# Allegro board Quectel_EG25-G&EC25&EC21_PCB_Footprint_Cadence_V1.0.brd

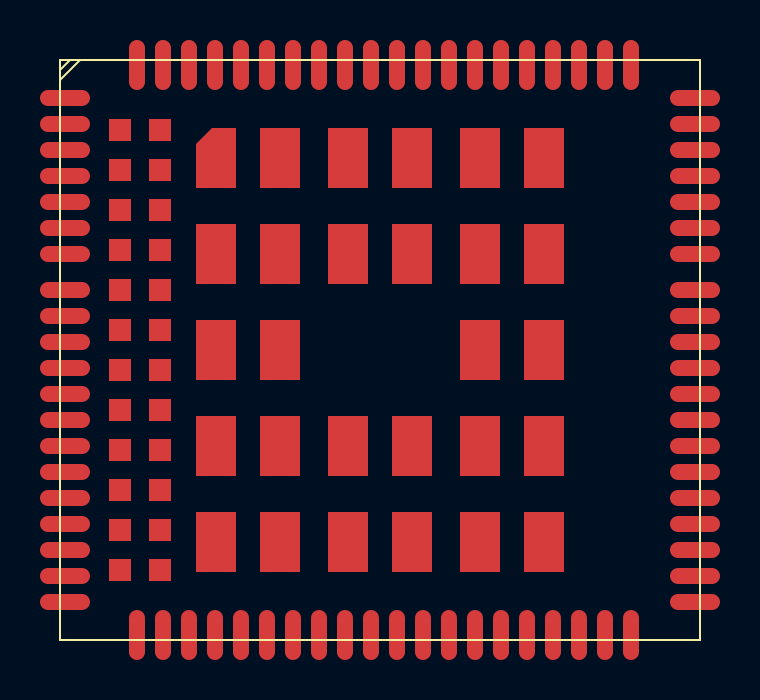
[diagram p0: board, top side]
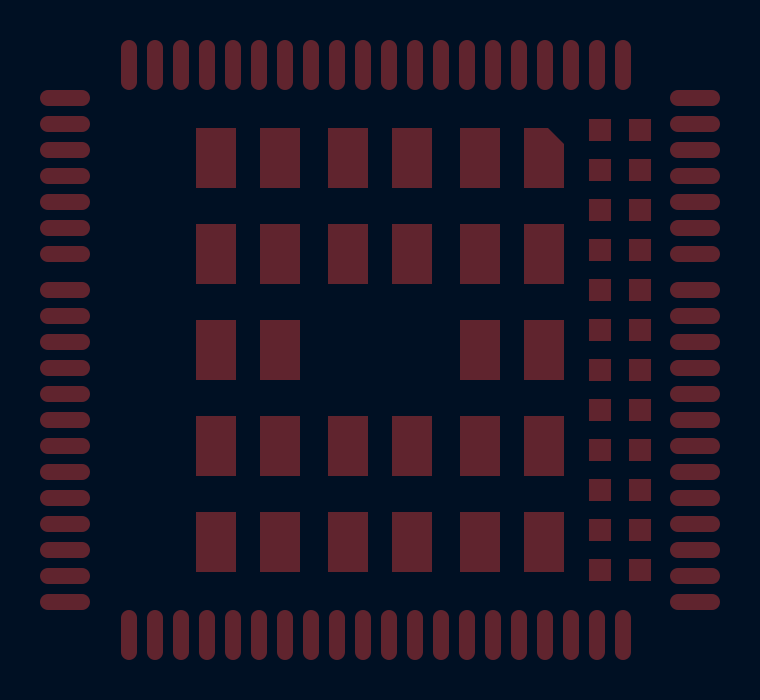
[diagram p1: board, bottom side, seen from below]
No outline. copper layers: TOP, BOTTOM. Coordinates in mm from the lowest, leftmost part position.

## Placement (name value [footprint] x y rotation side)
NOREF  -  [unnamed]  0 0 0 top

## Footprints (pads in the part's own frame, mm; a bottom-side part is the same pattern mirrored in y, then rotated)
unnamed
  oval 2.5x0.8 smd: 1(-15.75,12.6) 2(-15.75,11.3) 3(-15.75,10) 4(-15.75,8.7) 5(-15.75,7.4) 6(-15.75,6.1) 7(-15.75,4.8) 8(-15.75,0.4) 9(-15.75,-0.9) 10(-15.75,-2.2) 11(-15.75,-3.5) 12(-15.75,-4.8) 13(-15.75,-6.1) 14(-15.75,-7.4) 15(-15.75,-8.7) 16(-15.75,-10) 17(-15.75,-11.3) 18(-15.75,-12.6) 37(15.75,-12.6) 38(15.75,-11.3) 39(15.75,-10) 40(15.75,-8.7) 41(15.75,-7.4) 42(15.75,-6.1) 43(15.75,-4.8) 44(15.75,-3.5) 45(15.75,-2.2) 46(15.75,-0.9) 47(15.75,0.4) 48(15.75,4.8) 49(15.75,6.1) 50(15.75,7.4) 51(15.75,8.7) 52(15.75,10) 53(15.75,11.3) 54(15.75,12.6) 141(-15.75,3) 142(-15.75,1.7) 143(15.75,1.7) 144(15.75,3)
  oval 0.8x2.5 smd: 19(-9.55,-14.25) 20(-8.25,-14.25) 21(-6.95,-14.25) 22(-5.65,-14.25) 23(-4.35,-14.25) 24(-3.05,-14.25) 25(-1.75,-14.25) 26(-0.45,-14.25) 27(0.85,-14.25) 28(2.15,-14.25) 29(3.45,-14.25) 30(4.75,-14.25) 31(6.05,-14.25) 32(7.35,-14.25) 33(8.65,-14.25) 34(9.95,-14.25) 35(11.25,-14.25) 36(12.55,-14.25) 55(12.55,14.25) 56(11.25,14.25) 57(9.95,14.25) 58(8.65,14.25) 59(7.35,14.25) 60(6.05,14.25) 61(4.75,14.25) 62(3.45,14.25) 63(2.15,14.25) 64(0.85,14.25) 65(-0.45,14.25) 66(-1.75,14.25) 67(-3.05,14.25) 68(-4.35,14.25) 69(-5.65,14.25) 70(-6.95,14.25) 71(-8.25,14.25) 72(-9.55,14.25) 113(-10.85,14.25) 114(-12.15,14.25) 115(-10.85,-14.25) 116(-12.15,-14.25)
  rect 2x3 smd: 85(8.2,9.6) 86(8.2,4.8) 87(8.2,0) 88(8.2,-4.8) 89(8.2,-9.6) 90(5,9.6) 91(5,4.8) 92(5,0) 93(5,-4.8) 94(5,-9.6) 95(1.6,9.6) 96(1.6,4.8) 97(1.6,-4.8) 98(1.6,-9.6) 99(-1.6,9.6) 100(-1.6,4.8) 101(-1.6,-4.8) 102(-1.6,-9.6) 103(-5,9.6) 104(-5,4.8) 105(-5,0) 106(-5,-4.8) 107(-5,-9.6) 109(-8.2,4.8) 110(-8.2,0) 111(-8.2,-4.8) 112(-8.2,-9.6)
  custom 0.5x0.5 smd: 108(-8.2,9.6)
  rect 1.1x1.1 smd: 117(-11,11) 118(-11,9) 119(-11,7) 120(-11,5) 121(-11,3) 122(-11,1) 123(-11,-1) 124(-11,-3) 125(-11,-5) 126(-11,-7) 127(-11,-9) 128(-11,-11) 129(-13,11) 130(-13,9) 131(-13,7) 132(-13,5) 133(-13,3) 134(-13,1) 135(-13,-1) 136(-13,-3) 137(-13,-5) 138(-13,-7) 139(-13,-9) 140(-13,-11)

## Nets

Pads without a net: NOREF 1 2 3 4 5 6 7 8 9 10 11 12 13 14 15 16 17 18 19 20 21 22 23 24 25 26 27 28 29 30 31 32 33 34 35 36 37 38 39 40 41 42 43 44 45 46 47 48 49 50 51 52 53 54 55 56 57 58 59 60 61 62 63 64 65 66 67 68 69 70 71 72 85 86 87 88 89 90 91 92 93 94 95 96 97 98 99 100 101 102 103 104 105 106 107 108 109 110 111 112 113 114 115 116 117 118 119 120 121 122 123 124 125 126 127 128 129 130 131 132 133 134 135 136 137 138 139 140 141 142 143 144
